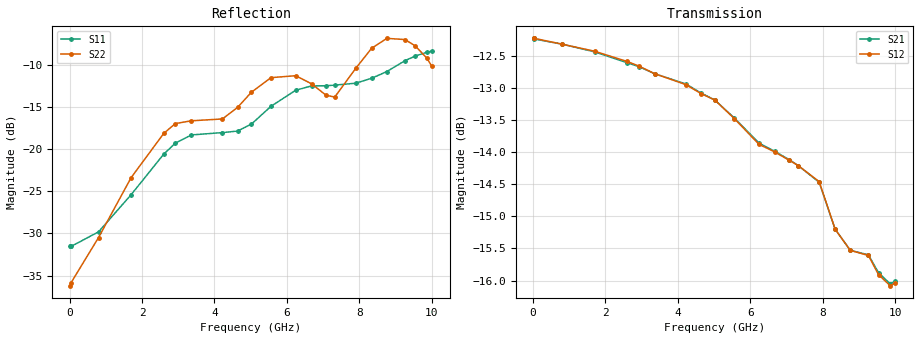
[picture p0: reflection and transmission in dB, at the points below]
! Integrated Device Technology
! Corporate Headquarters
! 6024 Silver Creek Valley Road
! San Jose, CA 95138  USA
! Phone:  1-408-284-8200
! Toll Free:  1-800-223-1366
! Webpage:  http://www.idt.com/
! Timing and RF Division
! 515 Groton Road, Suite 102
! Westford, MA 01886-6024
! Device:  F1958
! Description: 7-bit 0.25 dB Digital Step Attenuator
! Frequency:  0.001 -  6.000 GHz
! Package:  4x4 mm Thin QFN Plastic Package: 24 pin
! Ports:  2 RF, 12 DC
!  Pin  1  = D0
!  Pin  2  = VDD
!  Pin  3  = VMODE
!  Pin  4  = GND
!  Pin  5  = RF1  =  Port 1
!  Pin  6  = GND
!  Pin  7  = GND
!  Pin  8  = GND
!  Pin  9  = GND
!  Pin 10  = GND
!  Pin 11  = GND
!  Pin 12  = GND
!  Pin 13  = GND
!  Pin 14  = RF2  =  Port 2
!  Pin 15  = GND
!  Pin 16  = LE
!  Pin 17  = CLK
!  Pin 18  = DATA
!  Pin 19  = D6
!  Pin 20  = D5
!  Pin 21  = D4
!  Pin 22  = D3
!  Pin 23  = D2
!  Pin 24  = D1
! State:  45
! Atten State:  11.25 dB
! Voltage:  +3.30 Volts
! Current:  0.258 mA
! Data:  The device was measured on a F1958 evaluation board which has
!  individual transmission lines to the RF pins.  Data was collected
!  using a calibrated network analyzer.  The evaluation board was
!  de-embedded using Automatic Fixture Removal (AFR).
!  The reference plane is the edge of the package pin.
! Misc:
!  Action Tracker AT0419
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# GHz S dB R 50
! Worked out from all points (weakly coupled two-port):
!   500 points, 20 MHz to 10 GHz, reference 50 ohm
!   highest |S21| = -12.23 dB at 20 MHz (marker M1); lowest = -16.0 dB at 9.86 GHz (marker M2)
!   lowest |S11| = -31.5 dB at 40 MHz (marker M3), VSWR 1.05, Z = 47.4 - j0.0647 ohm
!   |S11| at or under -10 dB: start of sweep to 9.045 GHz
!   |S22| runs from -36.2 to -6.8 dB; largest |S21 - S12| = 0.00067
!   S11 on the Smith chart (normalised r, x): 20 MHz: 0.95, -0.00; 6.24 GHz: 0.66, +0.17; 10 GHz: 0.68, +0.60
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0.02  -31.51 -178.5  -12.23 -0.5  -12.23 -0.5  -36.21 -173.8
0.04  -31.55 -178.5  -12.24 -0.9  -12.23 -0.9  -35.87 -171.2
0.8  -29.81 174.8  -12.32 -15.2  -12.32 -15.2  -30.49 -161.7
1.7  -25.39 175.6  -12.44 -32.1  -12.43 -32.1  -23.36 -169.3
2.6  -20.57 -178.9  -12.61 -49.0  -12.59 -49.0  -18.11 -174.8
2.92  -19.27 -175.8  -12.67 -55.0  -12.66 -55.1  -16.94 -175.2
3.36  -18.29 -173.0  -12.78 -63.2  -12.78 -63.3  -16.61 -176.9
4.22  -18.01 -176.4  -12.94 -79.3  -12.95 -79.4  -16.39 155.9
4.64  -17.83 174.0  -13.08 -87.2  -13.09 -87.2  -15.01 140.5
5.02  -17.00 162.9  -13.19 -94.5  -13.19 -94.5  -13.21 130.7
5.56  -14.89 151.9  -13.47 -104.7  -13.48 -104.6  -11.48 128.2
6.24  -12.98 148.0  -13.86 -116.8  -13.88 -116.8  -11.25 132.5
6.68  -12.46 146.0  -13.99 -124.8  -14.00 -124.7  -12.21 127.3
7.08  -12.44 142.6  -14.12 -133.2  -14.13 -133.1  -13.57 109.7
7.32  -12.37 140.5  -14.21 -137.5  -14.21 -137.3  -13.79 93.2
7.9  -12.14 128.6  -14.47 -149.7  -14.46 -149.7  -10.37 66.4
8.34  -11.55 119.1  -15.20 -157.7  -15.20 -157.7  -7.98 63.4
8.76  -10.75 111.0  -15.53 -161.6  -15.53 -161.5  -6.81 67.4
9.26  -9.46 103.8  -15.60 -170.4  -15.61 -170.4  -6.95 76.5
9.54  -8.92 100.9  -15.88 -174.4  -15.91 -174.4  -7.70 78.8
9.86  -8.46 98.8  -16.05 -178.4  -16.08 -178.3  -9.15 77.0
10  -8.34 98.8  -16.01 179.4  -16.04 179.5  -10.12 73.9
